VERSION 5.7 ;
  NOWIREEXTENSIONATPIN ON ;
  DIVIDERCHAR "/" ;
  BUSBITCHARS "[]" ;
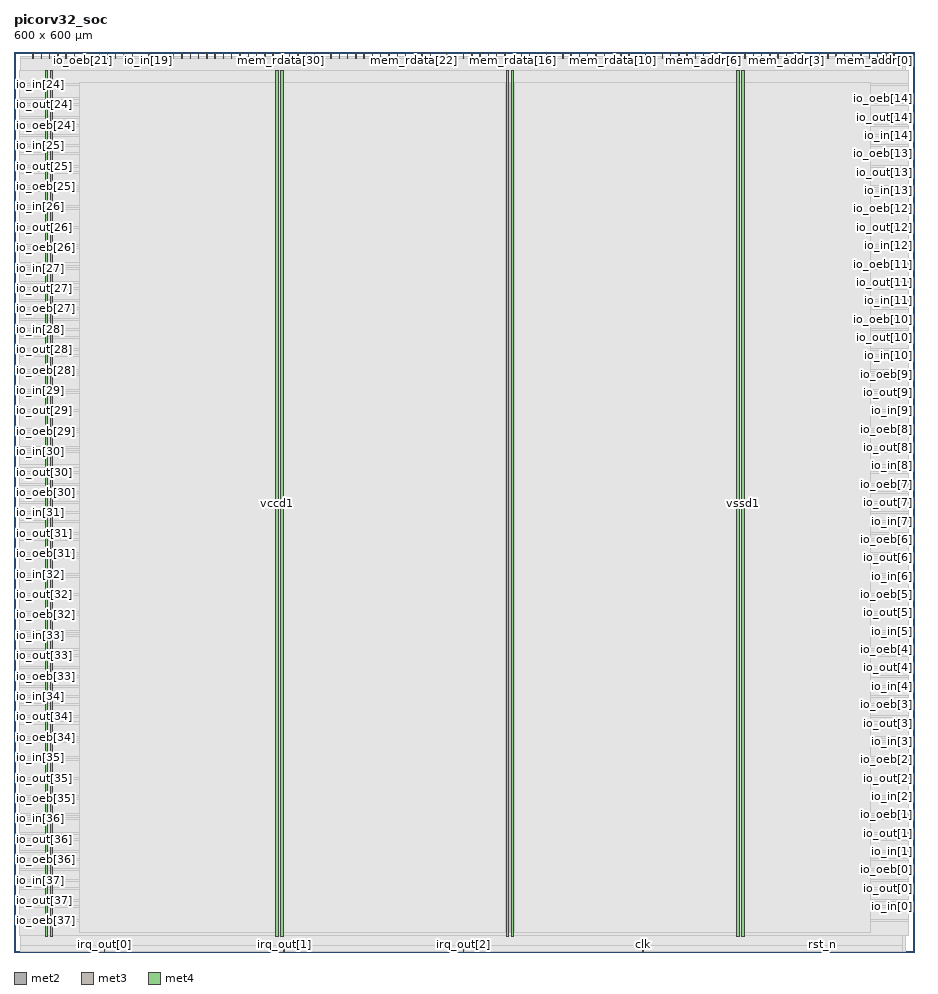
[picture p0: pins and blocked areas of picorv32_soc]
MACRO picorv32_soc
  CLASS BLOCK ;
  FOREIGN picorv32_soc ;
  ORIGIN 0.000 0.000 ;
  SIZE 600.000 BY 600.000 ;
  PIN clk
    DIRECTION INPUT ;
    USE SIGNAL ;
    ANTENNAGATEAREA 1.286700 ;
    ANTENNADIFFAREA 0.434700 ;
    PORT
      LAYER met2 ;
        RECT 419.150 0.000 419.430 4.000 ;
    END
  END clk
  PIN io_in[0]
    DIRECTION INPUT ;
    USE SIGNAL ;
    PORT
      LAYER met3 ;
        RECT 596.000 29.960 600.000 30.560 ;
    END
  END io_in[0]
  PIN io_in[10]
    DIRECTION INPUT ;
    USE SIGNAL ;
    PORT
      LAYER met3 ;
        RECT 596.000 397.160 600.000 397.760 ;
    END
  END io_in[10]
  PIN io_in[11]
    DIRECTION INPUT ;
    USE SIGNAL ;
    PORT
      LAYER met3 ;
        RECT 596.000 433.880 600.000 434.480 ;
    END
  END io_in[11]
  PIN io_in[12]
    DIRECTION INPUT ;
    USE SIGNAL ;
    PORT
      LAYER met3 ;
        RECT 596.000 470.600 600.000 471.200 ;
    END
  END io_in[12]
  PIN io_in[13]
    DIRECTION INPUT ;
    USE SIGNAL ;
    PORT
      LAYER met3 ;
        RECT 596.000 507.320 600.000 507.920 ;
    END
  END io_in[13]
  PIN io_in[14]
    DIRECTION INPUT ;
    USE SIGNAL ;
    PORT
      LAYER met3 ;
        RECT 596.000 544.040 600.000 544.640 ;
    END
  END io_in[14]
  PIN io_in[15]
    DIRECTION INPUT ;
    USE SIGNAL ;
    PORT
      LAYER met2 ;
        RECT 156.030 596.000 156.310 600.000 ;
    END
  END io_in[15]
  PIN io_in[16]
    DIRECTION INPUT ;
    USE SIGNAL ;
    PORT
      LAYER met2 ;
        RECT 139.470 596.000 139.750 600.000 ;
    END
  END io_in[16]
  PIN io_in[17]
    DIRECTION INPUT ;
    USE SIGNAL ;
    PORT
      LAYER met2 ;
        RECT 122.910 596.000 123.190 600.000 ;
    END
  END io_in[17]
  PIN io_in[18]
    DIRECTION INPUT ;
    USE SIGNAL ;
    PORT
      LAYER met2 ;
        RECT 106.350 596.000 106.630 600.000 ;
    END
  END io_in[18]
  PIN io_in[19]
    DIRECTION INPUT ;
    USE SIGNAL ;
    PORT
      LAYER met2 ;
        RECT 89.790 596.000 90.070 600.000 ;
    END
  END io_in[19]
  PIN io_in[1]
    DIRECTION INPUT ;
    USE SIGNAL ;
    PORT
      LAYER met3 ;
        RECT 596.000 66.680 600.000 67.280 ;
    END
  END io_in[1]
  PIN io_in[20]
    DIRECTION INPUT ;
    USE SIGNAL ;
    PORT
      LAYER met2 ;
        RECT 73.230 596.000 73.510 600.000 ;
    END
  END io_in[20]
  PIN io_in[21]
    DIRECTION INPUT ;
    USE SIGNAL ;
    ANTENNAGATEAREA 0.631200 ;
    ANTENNADIFFAREA 0.434700 ;
    PORT
      LAYER met2 ;
        RECT 56.670 596.000 56.950 600.000 ;
    END
  END io_in[21]
  PIN io_in[22]
    DIRECTION INPUT ;
    USE SIGNAL ;
    PORT
      LAYER met2 ;
        RECT 40.110 596.000 40.390 600.000 ;
    END
  END io_in[22]
  PIN io_in[23]
    DIRECTION INPUT ;
    USE SIGNAL ;
    PORT
      LAYER met2 ;
        RECT 23.550 596.000 23.830 600.000 ;
    END
  END io_in[23]
  PIN io_in[24]
    DIRECTION INPUT ;
    USE SIGNAL ;
    PORT
      LAYER met3 ;
        RECT 0.000 578.040 4.000 578.640 ;
    END
  END io_in[24]
  PIN io_in[25]
    DIRECTION INPUT ;
    USE SIGNAL ;
    PORT
      LAYER met3 ;
        RECT 0.000 537.240 4.000 537.840 ;
    END
  END io_in[25]
  PIN io_in[26]
    DIRECTION INPUT ;
    USE SIGNAL ;
    PORT
      LAYER met3 ;
        RECT 0.000 496.440 4.000 497.040 ;
    END
  END io_in[26]
  PIN io_in[27]
    DIRECTION INPUT ;
    USE SIGNAL ;
    PORT
      LAYER met3 ;
        RECT 0.000 455.640 4.000 456.240 ;
    END
  END io_in[27]
  PIN io_in[28]
    DIRECTION INPUT ;
    USE SIGNAL ;
    PORT
      LAYER met3 ;
        RECT 0.000 414.840 4.000 415.440 ;
    END
  END io_in[28]
  PIN io_in[29]
    DIRECTION INPUT ;
    USE SIGNAL ;
    PORT
      LAYER met3 ;
        RECT 0.000 374.040 4.000 374.640 ;
    END
  END io_in[29]
  PIN io_in[2]
    DIRECTION INPUT ;
    USE SIGNAL ;
    PORT
      LAYER met3 ;
        RECT 596.000 103.400 600.000 104.000 ;
    END
  END io_in[2]
  PIN io_in[30]
    DIRECTION INPUT ;
    USE SIGNAL ;
    PORT
      LAYER met3 ;
        RECT 0.000 333.240 4.000 333.840 ;
    END
  END io_in[30]
  PIN io_in[31]
    DIRECTION INPUT ;
    USE SIGNAL ;
    PORT
      LAYER met3 ;
        RECT 0.000 292.440 4.000 293.040 ;
    END
  END io_in[31]
  PIN io_in[32]
    DIRECTION INPUT ;
    USE SIGNAL ;
    PORT
      LAYER met3 ;
        RECT 0.000 251.640 4.000 252.240 ;
    END
  END io_in[32]
  PIN io_in[33]
    DIRECTION INPUT ;
    USE SIGNAL ;
    PORT
      LAYER met3 ;
        RECT 0.000 210.840 4.000 211.440 ;
    END
  END io_in[33]
  PIN io_in[34]
    DIRECTION INPUT ;
    USE SIGNAL ;
    PORT
      LAYER met3 ;
        RECT 0.000 170.040 4.000 170.640 ;
    END
  END io_in[34]
  PIN io_in[35]
    DIRECTION INPUT ;
    USE SIGNAL ;
    PORT
      LAYER met3 ;
        RECT 0.000 129.240 4.000 129.840 ;
    END
  END io_in[35]
  PIN io_in[36]
    DIRECTION INPUT ;
    USE SIGNAL ;
    PORT
      LAYER met3 ;
        RECT 0.000 88.440 4.000 89.040 ;
    END
  END io_in[36]
  PIN io_in[37]
    DIRECTION INPUT ;
    USE SIGNAL ;
    PORT
      LAYER met3 ;
        RECT 0.000 47.640 4.000 48.240 ;
    END
  END io_in[37]
  PIN io_in[3]
    DIRECTION INPUT ;
    USE SIGNAL ;
    PORT
      LAYER met3 ;
        RECT 596.000 140.120 600.000 140.720 ;
    END
  END io_in[3]
  PIN io_in[4]
    DIRECTION INPUT ;
    USE SIGNAL ;
    PORT
      LAYER met3 ;
        RECT 596.000 176.840 600.000 177.440 ;
    END
  END io_in[4]
  PIN io_in[5]
    DIRECTION INPUT ;
    USE SIGNAL ;
    PORT
      LAYER met3 ;
        RECT 596.000 213.560 600.000 214.160 ;
    END
  END io_in[5]
  PIN io_in[6]
    DIRECTION INPUT ;
    USE SIGNAL ;
    PORT
      LAYER met3 ;
        RECT 596.000 250.280 600.000 250.880 ;
    END
  END io_in[6]
  PIN io_in[7]
    DIRECTION INPUT ;
    USE SIGNAL ;
    PORT
      LAYER met3 ;
        RECT 596.000 287.000 600.000 287.600 ;
    END
  END io_in[7]
  PIN io_in[8]
    DIRECTION INPUT ;
    USE SIGNAL ;
    PORT
      LAYER met3 ;
        RECT 596.000 323.720 600.000 324.320 ;
    END
  END io_in[8]
  PIN io_in[9]
    DIRECTION INPUT ;
    USE SIGNAL ;
    PORT
      LAYER met3 ;
        RECT 596.000 360.440 600.000 361.040 ;
    END
  END io_in[9]
  PIN io_oeb[0]
    DIRECTION OUTPUT ;
    USE SIGNAL ;
    PORT
      LAYER met3 ;
        RECT 596.000 54.440 600.000 55.040 ;
    END
  END io_oeb[0]
  PIN io_oeb[10]
    DIRECTION OUTPUT ;
    USE SIGNAL ;
    PORT
      LAYER met3 ;
        RECT 596.000 421.640 600.000 422.240 ;
    END
  END io_oeb[10]
  PIN io_oeb[11]
    DIRECTION OUTPUT ;
    USE SIGNAL ;
    PORT
      LAYER met3 ;
        RECT 596.000 458.360 600.000 458.960 ;
    END
  END io_oeb[11]
  PIN io_oeb[12]
    DIRECTION OUTPUT ;
    USE SIGNAL ;
    PORT
      LAYER met3 ;
        RECT 596.000 495.080 600.000 495.680 ;
    END
  END io_oeb[12]
  PIN io_oeb[13]
    DIRECTION OUTPUT ;
    USE SIGNAL ;
    PORT
      LAYER met3 ;
        RECT 596.000 531.800 600.000 532.400 ;
    END
  END io_oeb[13]
  PIN io_oeb[14]
    DIRECTION OUTPUT ;
    USE SIGNAL ;
    PORT
      LAYER met3 ;
        RECT 596.000 568.520 600.000 569.120 ;
    END
  END io_oeb[14]
  PIN io_oeb[15]
    DIRECTION OUTPUT ;
    USE SIGNAL ;
    PORT
      LAYER met2 ;
        RECT 144.990 596.000 145.270 600.000 ;
    END
  END io_oeb[15]
  PIN io_oeb[16]
    DIRECTION OUTPUT ;
    USE SIGNAL ;
    PORT
      LAYER met2 ;
        RECT 128.430 596.000 128.710 600.000 ;
    END
  END io_oeb[16]
  PIN io_oeb[17]
    DIRECTION OUTPUT ;
    USE SIGNAL ;
    PORT
      LAYER met2 ;
        RECT 111.870 596.000 112.150 600.000 ;
    END
  END io_oeb[17]
  PIN io_oeb[18]
    DIRECTION OUTPUT ;
    USE SIGNAL ;
    PORT
      LAYER met2 ;
        RECT 95.310 596.000 95.590 600.000 ;
    END
  END io_oeb[18]
  PIN io_oeb[19]
    DIRECTION OUTPUT ;
    USE SIGNAL ;
    PORT
      LAYER met2 ;
        RECT 78.750 596.000 79.030 600.000 ;
    END
  END io_oeb[19]
  PIN io_oeb[1]
    DIRECTION OUTPUT ;
    USE SIGNAL ;
    PORT
      LAYER met3 ;
        RECT 596.000 91.160 600.000 91.760 ;
    END
  END io_oeb[1]
  PIN io_oeb[20]
    DIRECTION OUTPUT ;
    USE SIGNAL ;
    PORT
      LAYER met2 ;
        RECT 62.190 596.000 62.470 600.000 ;
    END
  END io_oeb[20]
  PIN io_oeb[21]
    DIRECTION OUTPUT ;
    USE SIGNAL ;
    PORT
      LAYER met2 ;
        RECT 45.630 596.000 45.910 600.000 ;
    END
  END io_oeb[21]
  PIN io_oeb[22]
    DIRECTION OUTPUT ;
    USE SIGNAL ;
    PORT
      LAYER met2 ;
        RECT 29.070 596.000 29.350 600.000 ;
    END
  END io_oeb[22]
  PIN io_oeb[23]
    DIRECTION OUTPUT ;
    USE SIGNAL ;
    PORT
      LAYER met2 ;
        RECT 12.510 596.000 12.790 600.000 ;
    END
  END io_oeb[23]
  PIN io_oeb[24]
    DIRECTION OUTPUT ;
    USE SIGNAL ;
    PORT
      LAYER met3 ;
        RECT 0.000 550.840 4.000 551.440 ;
    END
  END io_oeb[24]
  PIN io_oeb[25]
    DIRECTION OUTPUT ;
    USE SIGNAL ;
    PORT
      LAYER met3 ;
        RECT 0.000 510.040 4.000 510.640 ;
    END
  END io_oeb[25]
  PIN io_oeb[26]
    DIRECTION OUTPUT ;
    USE SIGNAL ;
    PORT
      LAYER met3 ;
        RECT 0.000 469.240 4.000 469.840 ;
    END
  END io_oeb[26]
  PIN io_oeb[27]
    DIRECTION OUTPUT ;
    USE SIGNAL ;
    PORT
      LAYER met3 ;
        RECT 0.000 428.440 4.000 429.040 ;
    END
  END io_oeb[27]
  PIN io_oeb[28]
    DIRECTION OUTPUT ;
    USE SIGNAL ;
    PORT
      LAYER met3 ;
        RECT 0.000 387.640 4.000 388.240 ;
    END
  END io_oeb[28]
  PIN io_oeb[29]
    DIRECTION OUTPUT ;
    USE SIGNAL ;
    PORT
      LAYER met3 ;
        RECT 0.000 346.840 4.000 347.440 ;
    END
  END io_oeb[29]
  PIN io_oeb[2]
    DIRECTION OUTPUT ;
    USE SIGNAL ;
    PORT
      LAYER met3 ;
        RECT 596.000 127.880 600.000 128.480 ;
    END
  END io_oeb[2]
  PIN io_oeb[30]
    DIRECTION OUTPUT ;
    USE SIGNAL ;
    PORT
      LAYER met3 ;
        RECT 0.000 306.040 4.000 306.640 ;
    END
  END io_oeb[30]
  PIN io_oeb[31]
    DIRECTION OUTPUT ;
    USE SIGNAL ;
    PORT
      LAYER met3 ;
        RECT 0.000 265.240 4.000 265.840 ;
    END
  END io_oeb[31]
  PIN io_oeb[32]
    DIRECTION OUTPUT ;
    USE SIGNAL ;
    PORT
      LAYER met3 ;
        RECT 0.000 224.440 4.000 225.040 ;
    END
  END io_oeb[32]
  PIN io_oeb[33]
    DIRECTION OUTPUT ;
    USE SIGNAL ;
    PORT
      LAYER met3 ;
        RECT 0.000 183.640 4.000 184.240 ;
    END
  END io_oeb[33]
  PIN io_oeb[34]
    DIRECTION OUTPUT ;
    USE SIGNAL ;
    PORT
      LAYER met3 ;
        RECT 0.000 142.840 4.000 143.440 ;
    END
  END io_oeb[34]
  PIN io_oeb[35]
    DIRECTION OUTPUT ;
    USE SIGNAL ;
    PORT
      LAYER met3 ;
        RECT 0.000 102.040 4.000 102.640 ;
    END
  END io_oeb[35]
  PIN io_oeb[36]
    DIRECTION OUTPUT ;
    USE SIGNAL ;
    PORT
      LAYER met3 ;
        RECT 0.000 61.240 4.000 61.840 ;
    END
  END io_oeb[36]
  PIN io_oeb[37]
    DIRECTION OUTPUT ;
    USE SIGNAL ;
    PORT
      LAYER met3 ;
        RECT 0.000 20.440 4.000 21.040 ;
    END
  END io_oeb[37]
  PIN io_oeb[3]
    DIRECTION OUTPUT ;
    USE SIGNAL ;
    PORT
      LAYER met3 ;
        RECT 596.000 164.600 600.000 165.200 ;
    END
  END io_oeb[3]
  PIN io_oeb[4]
    DIRECTION OUTPUT ;
    USE SIGNAL ;
    PORT
      LAYER met3 ;
        RECT 596.000 201.320 600.000 201.920 ;
    END
  END io_oeb[4]
  PIN io_oeb[5]
    DIRECTION OUTPUT ;
    USE SIGNAL ;
    PORT
      LAYER met3 ;
        RECT 596.000 238.040 600.000 238.640 ;
    END
  END io_oeb[5]
  PIN io_oeb[6]
    DIRECTION OUTPUT ;
    USE SIGNAL ;
    PORT
      LAYER met3 ;
        RECT 596.000 274.760 600.000 275.360 ;
    END
  END io_oeb[6]
  PIN io_oeb[7]
    DIRECTION OUTPUT ;
    USE SIGNAL ;
    PORT
      LAYER met3 ;
        RECT 596.000 311.480 600.000 312.080 ;
    END
  END io_oeb[7]
  PIN io_oeb[8]
    DIRECTION OUTPUT ;
    USE SIGNAL ;
    PORT
      LAYER met3 ;
        RECT 596.000 348.200 600.000 348.800 ;
    END
  END io_oeb[8]
  PIN io_oeb[9]
    DIRECTION OUTPUT ;
    USE SIGNAL ;
    PORT
      LAYER met3 ;
        RECT 596.000 384.920 600.000 385.520 ;
    END
  END io_oeb[9]
  PIN io_out[0]
    DIRECTION OUTPUT ;
    USE SIGNAL ;
    PORT
      LAYER met3 ;
        RECT 596.000 42.200 600.000 42.800 ;
    END
  END io_out[0]
  PIN io_out[10]
    DIRECTION OUTPUT ;
    USE SIGNAL ;
    PORT
      LAYER met3 ;
        RECT 596.000 409.400 600.000 410.000 ;
    END
  END io_out[10]
  PIN io_out[11]
    DIRECTION OUTPUT ;
    USE SIGNAL ;
    PORT
      LAYER met3 ;
        RECT 596.000 446.120 600.000 446.720 ;
    END
  END io_out[11]
  PIN io_out[12]
    DIRECTION OUTPUT ;
    USE SIGNAL ;
    PORT
      LAYER met3 ;
        RECT 596.000 482.840 600.000 483.440 ;
    END
  END io_out[12]
  PIN io_out[13]
    DIRECTION OUTPUT ;
    USE SIGNAL ;
    PORT
      LAYER met3 ;
        RECT 596.000 519.560 600.000 520.160 ;
    END
  END io_out[13]
  PIN io_out[14]
    DIRECTION OUTPUT ;
    USE SIGNAL ;
    PORT
      LAYER met3 ;
        RECT 596.000 556.280 600.000 556.880 ;
    END
  END io_out[14]
  PIN io_out[15]
    DIRECTION OUTPUT ;
    USE SIGNAL ;
    PORT
      LAYER met2 ;
        RECT 150.510 596.000 150.790 600.000 ;
    END
  END io_out[15]
  PIN io_out[16]
    DIRECTION OUTPUT ;
    USE SIGNAL ;
    PORT
      LAYER met2 ;
        RECT 133.950 596.000 134.230 600.000 ;
    END
  END io_out[16]
  PIN io_out[17]
    DIRECTION OUTPUT ;
    USE SIGNAL ;
    PORT
      LAYER met2 ;
        RECT 117.390 596.000 117.670 600.000 ;
    END
  END io_out[17]
  PIN io_out[18]
    DIRECTION OUTPUT ;
    USE SIGNAL ;
    PORT
      LAYER met2 ;
        RECT 100.830 596.000 101.110 600.000 ;
    END
  END io_out[18]
  PIN io_out[19]
    DIRECTION OUTPUT ;
    USE SIGNAL ;
    PORT
      LAYER met2 ;
        RECT 84.270 596.000 84.550 600.000 ;
    END
  END io_out[19]
  PIN io_out[1]
    DIRECTION OUTPUT ;
    USE SIGNAL ;
    PORT
      LAYER met3 ;
        RECT 596.000 78.920 600.000 79.520 ;
    END
  END io_out[1]
  PIN io_out[20]
    DIRECTION OUTPUT ;
    USE SIGNAL ;
    ANTENNADIFFAREA 2.673000 ;
    PORT
      LAYER met2 ;
        RECT 67.710 596.000 67.990 600.000 ;
    END
  END io_out[20]
  PIN io_out[21]
    DIRECTION OUTPUT ;
    USE SIGNAL ;
    PORT
      LAYER met2 ;
        RECT 51.150 596.000 51.430 600.000 ;
    END
  END io_out[21]
  PIN io_out[22]
    DIRECTION OUTPUT ;
    USE SIGNAL ;
    PORT
      LAYER met2 ;
        RECT 34.590 596.000 34.870 600.000 ;
    END
  END io_out[22]
  PIN io_out[23]
    DIRECTION OUTPUT ;
    USE SIGNAL ;
    PORT
      LAYER met2 ;
        RECT 18.030 596.000 18.310 600.000 ;
    END
  END io_out[23]
  PIN io_out[24]
    DIRECTION OUTPUT ;
    USE SIGNAL ;
    PORT
      LAYER met3 ;
        RECT 0.000 564.440 4.000 565.040 ;
    END
  END io_out[24]
  PIN io_out[25]
    DIRECTION OUTPUT ;
    USE SIGNAL ;
    PORT
      LAYER met3 ;
        RECT 0.000 523.640 4.000 524.240 ;
    END
  END io_out[25]
  PIN io_out[26]
    DIRECTION OUTPUT ;
    USE SIGNAL ;
    PORT
      LAYER met3 ;
        RECT 0.000 482.840 4.000 483.440 ;
    END
  END io_out[26]
  PIN io_out[27]
    DIRECTION OUTPUT ;
    USE SIGNAL ;
    PORT
      LAYER met3 ;
        RECT 0.000 442.040 4.000 442.640 ;
    END
  END io_out[27]
  PIN io_out[28]
    DIRECTION OUTPUT ;
    USE SIGNAL ;
    PORT
      LAYER met3 ;
        RECT 0.000 401.240 4.000 401.840 ;
    END
  END io_out[28]
  PIN io_out[29]
    DIRECTION OUTPUT ;
    USE SIGNAL ;
    PORT
      LAYER met3 ;
        RECT 0.000 360.440 4.000 361.040 ;
    END
  END io_out[29]
  PIN io_out[2]
    DIRECTION OUTPUT ;
    USE SIGNAL ;
    PORT
      LAYER met3 ;
        RECT 596.000 115.640 600.000 116.240 ;
    END
  END io_out[2]
  PIN io_out[30]
    DIRECTION OUTPUT ;
    USE SIGNAL ;
    PORT
      LAYER met3 ;
        RECT 0.000 319.640 4.000 320.240 ;
    END
  END io_out[30]
  PIN io_out[31]
    DIRECTION OUTPUT ;
    USE SIGNAL ;
    PORT
      LAYER met3 ;
        RECT 0.000 278.840 4.000 279.440 ;
    END
  END io_out[31]
  PIN io_out[32]
    DIRECTION OUTPUT ;
    USE SIGNAL ;
    PORT
      LAYER met3 ;
        RECT 0.000 238.040 4.000 238.640 ;
    END
  END io_out[32]
  PIN io_out[33]
    DIRECTION OUTPUT ;
    USE SIGNAL ;
    PORT
      LAYER met3 ;
        RECT 0.000 197.240 4.000 197.840 ;
    END
  END io_out[33]
  PIN io_out[34]
    DIRECTION OUTPUT ;
    USE SIGNAL ;
    PORT
      LAYER met3 ;
        RECT 0.000 156.440 4.000 157.040 ;
    END
  END io_out[34]
  PIN io_out[35]
    DIRECTION OUTPUT ;
    USE SIGNAL ;
    PORT
      LAYER met3 ;
        RECT 0.000 115.640 4.000 116.240 ;
    END
  END io_out[35]
  PIN io_out[36]
    DIRECTION OUTPUT ;
    USE SIGNAL ;
    PORT
      LAYER met3 ;
        RECT 0.000 74.840 4.000 75.440 ;
    END
  END io_out[36]
  PIN io_out[37]
    DIRECTION OUTPUT ;
    USE SIGNAL ;
    PORT
      LAYER met3 ;
        RECT 0.000 34.040 4.000 34.640 ;
    END
  END io_out[37]
  PIN io_out[3]
    DIRECTION OUTPUT ;
    USE SIGNAL ;
    PORT
      LAYER met3 ;
        RECT 596.000 152.360 600.000 152.960 ;
    END
  END io_out[3]
  PIN io_out[4]
    DIRECTION OUTPUT ;
    USE SIGNAL ;
    PORT
      LAYER met3 ;
        RECT 596.000 189.080 600.000 189.680 ;
    END
  END io_out[4]
  PIN io_out[5]
    DIRECTION OUTPUT ;
    USE SIGNAL ;
    PORT
      LAYER met3 ;
        RECT 596.000 225.800 600.000 226.400 ;
    END
  END io_out[5]
  PIN io_out[6]
    DIRECTION OUTPUT ;
    USE SIGNAL ;
    PORT
      LAYER met3 ;
        RECT 596.000 262.520 600.000 263.120 ;
    END
  END io_out[6]
  PIN io_out[7]
    DIRECTION OUTPUT ;
    USE SIGNAL ;
    PORT
      LAYER met3 ;
        RECT 596.000 299.240 600.000 299.840 ;
    END
  END io_out[7]
  PIN io_out[8]
    DIRECTION OUTPUT ;
    USE SIGNAL ;
    PORT
      LAYER met3 ;
        RECT 596.000 335.960 600.000 336.560 ;
    END
  END io_out[8]
  PIN io_out[9]
    DIRECTION OUTPUT ;
    USE SIGNAL ;
    PORT
      LAYER met3 ;
        RECT 596.000 372.680 600.000 373.280 ;
    END
  END io_out[9]
  PIN irq_out[0]
    DIRECTION OUTPUT ;
    USE SIGNAL ;
    PORT
      LAYER met2 ;
        RECT 60.350 0.000 60.630 4.000 ;
    END
  END irq_out[0]
  PIN irq_out[1]
    DIRECTION OUTPUT ;
    USE SIGNAL ;
    ANTENNADIFFAREA 2.673000 ;
    PORT
      LAYER met2 ;
        RECT 179.950 0.000 180.230 4.000 ;
    END
  END irq_out[1]
  PIN irq_out[2]
    DIRECTION OUTPUT ;
    USE SIGNAL ;
    PORT
      LAYER met2 ;
        RECT 299.550 0.000 299.830 4.000 ;
    END
  END irq_out[2]
  PIN mem_addr[0]
    DIRECTION OUTPUT ;
    USE SIGNAL ;
    ANTENNADIFFAREA 2.673000 ;
    PORT
      LAYER met2 ;
        RECT 581.070 596.000 581.350 600.000 ;
    END
  END mem_addr[0]
  PIN mem_addr[1]
    DIRECTION OUTPUT ;
    USE SIGNAL ;
    ANTENNADIFFAREA 2.673000 ;
    PORT
      LAYER met2 ;
        RECT 558.990 596.000 559.270 600.000 ;
    END
  END mem_addr[1]
  PIN mem_addr[2]
    DIRECTION OUTPUT ;
    USE SIGNAL ;
    ANTENNADIFFAREA 2.673000 ;
    PORT
      LAYER met2 ;
        RECT 536.910 596.000 537.190 600.000 ;
    END
  END mem_addr[2]
  PIN mem_addr[3]
    DIRECTION OUTPUT ;
    USE SIGNAL ;
    ANTENNADIFFAREA 2.673000 ;
    PORT
      LAYER met2 ;
        RECT 514.830 596.000 515.110 600.000 ;
    END
  END mem_addr[3]
  PIN mem_addr[4]
    DIRECTION OUTPUT ;
    USE SIGNAL ;
    ANTENNADIFFAREA 2.673000 ;
    PORT
      LAYER met2 ;
        RECT 492.750 596.000 493.030 600.000 ;
    END
  END mem_addr[4]
  PIN mem_addr[5]
    DIRECTION OUTPUT ;
    USE SIGNAL ;
    ANTENNADIFFAREA 2.673000 ;
    PORT
      LAYER met2 ;
        RECT 476.190 596.000 476.470 600.000 ;
    END
  END mem_addr[5]
  PIN mem_addr[6]
    DIRECTION OUTPUT ;
    USE SIGNAL ;
    ANTENNADIFFAREA 2.673000 ;
    PORT
      LAYER met2 ;
        RECT 459.630 596.000 459.910 600.000 ;
    END
  END mem_addr[6]
  PIN mem_addr[7]
    DIRECTION OUTPUT ;
    USE SIGNAL ;
    ANTENNADIFFAREA 2.673000 ;
    PORT
      LAYER met2 ;
        RECT 443.070 596.000 443.350 600.000 ;
    END
  END mem_addr[7]
  PIN mem_addr[8]
    DIRECTION OUTPUT ;
    USE SIGNAL ;
    ANTENNADIFFAREA 2.673000 ;
    PORT
      LAYER met2 ;
        RECT 426.510 596.000 426.790 600.000 ;
    END
  END mem_addr[8]
  PIN mem_en
    DIRECTION OUTPUT ;
    USE SIGNAL ;
    ANTENNADIFFAREA 2.673000 ;
    PORT
      LAYER met2 ;
        RECT 586.590 596.000 586.870 600.000 ;
    END
  END mem_en
  PIN mem_rdata[0]
    DIRECTION INPUT ;
    USE SIGNAL ;
    ANTENNAGATEAREA 0.631200 ;
    ANTENNADIFFAREA 0.434700 ;
    PORT
      LAYER met2 ;
        RECT 575.550 596.000 575.830 600.000 ;
    END
  END mem_rdata[0]
  PIN mem_rdata[10]
    DIRECTION INPUT ;
    USE SIGNAL ;
    ANTENNAGATEAREA 0.631200 ;
    ANTENNADIFFAREA 0.434700 ;
    PORT
      LAYER met2 ;
        RECT 398.910 596.000 399.190 600.000 ;
    END
  END mem_rdata[10]
  PIN mem_rdata[11]
    DIRECTION INPUT ;
    USE SIGNAL ;
    ANTENNAGATEAREA 0.631200 ;
    ANTENNADIFFAREA 0.434700 ;
    PORT
      LAYER met2 ;
        RECT 387.870 596.000 388.150 600.000 ;
    END
  END mem_rdata[11]
  PIN mem_rdata[12]
    DIRECTION INPUT ;
    USE SIGNAL ;
    ANTENNAGATEAREA 0.631200 ;
    ANTENNADIFFAREA 0.434700 ;
    PORT
      LAYER met2 ;
        RECT 376.830 596.000 377.110 600.000 ;
    END
  END mem_rdata[12]
  PIN mem_rdata[13]
    DIRECTION INPUT ;
    USE SIGNAL ;
    ANTENNAGATEAREA 0.631200 ;
    ANTENNADIFFAREA 0.434700 ;
    PORT
      LAYER met2 ;
        RECT 365.790 596.000 366.070 600.000 ;
    END
  END mem_rdata[13]
  PIN mem_rdata[14]
    DIRECTION INPUT ;
    USE SIGNAL ;
    ANTENNAGATEAREA 0.631200 ;
    ANTENNADIFFAREA 0.434700 ;
    PORT
      LAYER met2 ;
        RECT 354.750 596.000 355.030 600.000 ;
    END
  END mem_rdata[14]
  PIN mem_rdata[15]
    DIRECTION INPUT ;
    USE SIGNAL ;
    ANTENNAGATEAREA 0.631200 ;
    ANTENNADIFFAREA 0.434700 ;
    PORT
      LAYER met2 ;
        RECT 343.710 596.000 343.990 600.000 ;
    END
  END mem_rdata[15]
  PIN mem_rdata[16]
    DIRECTION INPUT ;
    USE SIGNAL ;
    ANTENNAGATEAREA 0.631200 ;
    ANTENNADIFFAREA 0.434700 ;
    PORT
      LAYER met2 ;
        RECT 332.670 596.000 332.950 600.000 ;
    END
  END mem_rdata[16]
  PIN mem_rdata[17]
    DIRECTION INPUT ;
    USE SIGNAL ;
    ANTENNAGATEAREA 0.631200 ;
    ANTENNADIFFAREA 0.434700 ;
    PORT
      LAYER met2 ;
        RECT 321.630 596.000 321.910 600.000 ;
    END
  END mem_rdata[17]
  PIN mem_rdata[18]
    DIRECTION INPUT ;
    USE SIGNAL ;
    ANTENNAGATEAREA 0.631200 ;
    ANTENNADIFFAREA 0.434700 ;
    PORT
      LAYER met2 ;
        RECT 310.590 596.000 310.870 600.000 ;
    END
  END mem_rdata[18]
  PIN mem_rdata[19]
    DIRECTION INPUT ;
    USE SIGNAL ;
    ANTENNAGATEAREA 0.631200 ;
    ANTENNADIFFAREA 0.434700 ;
    PORT
      LAYER met2 ;
        RECT 299.550 596.000 299.830 600.000 ;
    END
  END mem_rdata[19]
  PIN mem_rdata[1]
    DIRECTION INPUT ;
    USE SIGNAL ;
    ANTENNAGATEAREA 0.631200 ;
    ANTENNADIFFAREA 0.434700 ;
    PORT
      LAYER met2 ;
        RECT 553.470 596.000 553.750 600.000 ;
    END
  END mem_rdata[1]
  PIN mem_rdata[20]
    DIRECTION INPUT ;
    USE SIGNAL ;
    ANTENNAGATEAREA 0.631200 ;
    ANTENNADIFFAREA 0.434700 ;
    PORT
      LAYER met2 ;
        RECT 288.510 596.000 288.790 600.000 ;
    END
  END mem_rdata[20]
  PIN mem_rdata[21]
    DIRECTION INPUT ;
    USE SIGNAL ;
    ANTENNAGATEAREA 0.631200 ;
    ANTENNADIFFAREA 0.434700 ;
    PORT
      LAYER met2 ;
        RECT 277.470 596.000 277.750 600.000 ;
    END
  END mem_rdata[21]
  PIN mem_rdata[22]
    DIRECTION INPUT ;
    USE SIGNAL ;
    ANTENNAGATEAREA 0.631200 ;
    ANTENNADIFFAREA 0.434700 ;
    PORT
      LAYER met2 ;
        RECT 266.430 596.000 266.710 600.000 ;
    END
  END mem_rdata[22]
  PIN mem_rdata[23]
    DIRECTION INPUT ;
    USE SIGNAL ;
    ANTENNAGATEAREA 0.631200 ;
    ANTENNADIFFAREA 0.434700 ;
    PORT
      LAYER met2 ;
        RECT 255.390 596.000 255.670 600.000 ;
    END
  END mem_rdata[23]
  PIN mem_rdata[24]
    DIRECTION INPUT ;
    USE SIGNAL ;
    ANTENNAGATEAREA 0.631200 ;
    ANTENNADIFFAREA 0.434700 ;
    PORT
      LAYER met2 ;
        RECT 244.350 596.000 244.630 600.000 ;
    END
  END mem_rdata[24]
  PIN mem_rdata[25]
    DIRECTION INPUT ;
    USE SIGNAL ;
    ANTENNAGATEAREA 0.631200 ;
    ANTENNADIFFAREA 0.434700 ;
    PORT
      LAYER met2 ;
        RECT 233.310 596.000 233.590 600.000 ;
    END
  END mem_rdata[25]
  PIN mem_rdata[26]
    DIRECTION INPUT ;
    USE SIGNAL ;
    ANTENNAGATEAREA 0.631200 ;
    ANTENNADIFFAREA 0.434700 ;
    PORT
      LAYER met2 ;
        RECT 222.270 596.000 222.550 600.000 ;
    END
  END mem_rdata[26]
  PIN mem_rdata[27]
    DIRECTION INPUT ;
    USE SIGNAL ;
    ANTENNAGATEAREA 0.631200 ;
    ANTENNADIFFAREA 0.434700 ;
    PORT
      LAYER met2 ;
        RECT 211.230 596.000 211.510 600.000 ;
    END
  END mem_rdata[27]
  PIN mem_rdata[28]
    DIRECTION INPUT ;
    USE SIGNAL ;
    ANTENNAGATEAREA 0.631200 ;
    ANTENNADIFFAREA 0.434700 ;
    PORT
      LAYER met2 ;
        RECT 200.190 596.000 200.470 600.000 ;
    END
  END mem_rdata[28]
  PIN mem_rdata[29]
    DIRECTION INPUT ;
    USE SIGNAL ;
    ANTENNAGATEAREA 0.631200 ;
    ANTENNADIFFAREA 0.434700 ;
    PORT
      LAYER met2 ;
        RECT 189.150 596.000 189.430 600.000 ;
    END
  END mem_rdata[29]
  PIN mem_rdata[2]
    DIRECTION INPUT ;
    USE SIGNAL ;
    ANTENNAGATEAREA 0.631200 ;
    ANTENNADIFFAREA 0.434700 ;
    PORT
      LAYER met2 ;
        RECT 531.390 596.000 531.670 600.000 ;
    END
  END mem_rdata[2]
  PIN mem_rdata[30]
    DIRECTION INPUT ;
    USE SIGNAL ;
    ANTENNAGATEAREA 0.631200 ;
    ANTENNADIFFAREA 0.434700 ;
    PORT
      LAYER met2 ;
        RECT 178.110 596.000 178.390 600.000 ;
    END
  END mem_rdata[30]
  PIN mem_rdata[31]
    DIRECTION INPUT ;
    USE SIGNAL ;
    ANTENNAGATEAREA 0.631200 ;
    ANTENNADIFFAREA 0.434700 ;
    PORT
      LAYER met2 ;
        RECT 167.070 596.000 167.350 600.000 ;
    END
  END mem_rdata[31]
  PIN mem_rdata[3]
    DIRECTION INPUT ;
    USE SIGNAL ;
    ANTENNAGATEAREA 0.631200 ;
    ANTENNADIFFAREA 0.434700 ;
    PORT
      LAYER met2 ;
        RECT 509.310 596.000 509.590 600.000 ;
    END
  END mem_rdata[3]
  PIN mem_rdata[4]
    DIRECTION INPUT ;
    USE SIGNAL ;
    ANTENNAGATEAREA 0.631200 ;
    ANTENNADIFFAREA 0.434700 ;
    PORT
      LAYER met2 ;
        RECT 487.230 596.000 487.510 600.000 ;
    END
  END mem_rdata[4]
  PIN mem_rdata[5]
    DIRECTION INPUT ;
    USE SIGNAL ;
    ANTENNAGATEAREA 0.631200 ;
    ANTENNADIFFAREA 0.434700 ;
    PORT
      LAYER met2 ;
        RECT 470.670 596.000 470.950 600.000 ;
    END
  END mem_rdata[5]
  PIN mem_rdata[6]
    DIRECTION INPUT ;
    USE SIGNAL ;
    ANTENNAGATEAREA 0.631200 ;
    ANTENNADIFFAREA 0.434700 ;
    PORT
      LAYER met2 ;
        RECT 454.110 596.000 454.390 600.000 ;
    END
  END mem_rdata[6]
  PIN mem_rdata[7]
    DIRECTION INPUT ;
    USE SIGNAL ;
    ANTENNAGATEAREA 0.631200 ;
    ANTENNADIFFAREA 0.434700 ;
    PORT
      LAYER met2 ;
        RECT 437.550 596.000 437.830 600.000 ;
    END
  END mem_rdata[7]
  PIN mem_rdata[8]
    DIRECTION INPUT ;
    USE SIGNAL ;
    ANTENNAGATEAREA 0.631200 ;
    ANTENNADIFFAREA 0.434700 ;
    PORT
      LAYER met2 ;
        RECT 420.990 596.000 421.270 600.000 ;
    END
  END mem_rdata[8]
  PIN mem_rdata[9]
    DIRECTION INPUT ;
    USE SIGNAL ;
    ANTENNAGATEAREA 0.631200 ;
    ANTENNADIFFAREA 0.434700 ;
    PORT
      LAYER met2 ;
        RECT 409.950 596.000 410.230 600.000 ;
    END
  END mem_rdata[9]
  PIN mem_wdata[0]
    DIRECTION OUTPUT ;
    USE SIGNAL ;
    ANTENNADIFFAREA 2.673000 ;
    PORT
      LAYER met2 ;
        RECT 570.030 596.000 570.310 600.000 ;
    END
  END mem_wdata[0]
  PIN mem_wdata[10]
    DIRECTION OUTPUT ;
    USE SIGNAL ;
    ANTENNADIFFAREA 2.673000 ;
    PORT
      LAYER met2 ;
        RECT 393.390 596.000 393.670 600.000 ;
    END
  END mem_wdata[10]
  PIN mem_wdata[11]
    DIRECTION OUTPUT ;
    USE SIGNAL ;
    ANTENNADIFFAREA 2.673000 ;
    PORT
      LAYER met2 ;
        RECT 382.350 596.000 382.630 600.000 ;
    END
  END mem_wdata[11]
  PIN mem_wdata[12]
    DIRECTION OUTPUT ;
    USE SIGNAL ;
    ANTENNADIFFAREA 2.673000 ;
    PORT
      LAYER met2 ;
        RECT 371.310 596.000 371.590 600.000 ;
    END
  END mem_wdata[12]
  PIN mem_wdata[13]
    DIRECTION OUTPUT ;
    USE SIGNAL ;
    ANTENNADIFFAREA 2.673000 ;
    PORT
      LAYER met2 ;
        RECT 360.270 596.000 360.550 600.000 ;
    END
  END mem_wdata[13]
  PIN mem_wdata[14]
    DIRECTION OUTPUT ;
    USE SIGNAL ;
    ANTENNADIFFAREA 2.673000 ;
    PORT
      LAYER met2 ;
        RECT 349.230 596.000 349.510 600.000 ;
    END
  END mem_wdata[14]
  PIN mem_wdata[15]
    DIRECTION OUTPUT ;
    USE SIGNAL ;
    ANTENNADIFFAREA 2.673000 ;
    PORT
      LAYER met2 ;
        RECT 338.190 596.000 338.470 600.000 ;
    END
  END mem_wdata[15]
  PIN mem_wdata[16]
    DIRECTION OUTPUT ;
    USE SIGNAL ;
    ANTENNADIFFAREA 2.673000 ;
    PORT
      LAYER met2 ;
        RECT 327.150 596.000 327.430 600.000 ;
    END
  END mem_wdata[16]
  PIN mem_wdata[17]
    DIRECTION OUTPUT ;
    USE SIGNAL ;
    ANTENNADIFFAREA 2.673000 ;
    PORT
      LAYER met2 ;
        RECT 316.110 596.000 316.390 600.000 ;
    END
  END mem_wdata[17]
  PIN mem_wdata[18]
    DIRECTION OUTPUT ;
    USE SIGNAL ;
    ANTENNADIFFAREA 2.673000 ;
    PORT
      LAYER met2 ;
        RECT 305.070 596.000 305.350 600.000 ;
    END
  END mem_wdata[18]
  PIN mem_wdata[19]
    DIRECTION OUTPUT ;
    USE SIGNAL ;
    ANTENNADIFFAREA 2.673000 ;
    PORT
      LAYER met2 ;
        RECT 294.030 596.000 294.310 600.000 ;
    END
  END mem_wdata[19]
  PIN mem_wdata[1]
    DIRECTION OUTPUT ;
    USE SIGNAL ;
    ANTENNADIFFAREA 2.673000 ;
    PORT
      LAYER met2 ;
        RECT 547.950 596.000 548.230 600.000 ;
    END
  END mem_wdata[1]
  PIN mem_wdata[20]
    DIRECTION OUTPUT ;
    USE SIGNAL ;
    ANTENNADIFFAREA 2.673000 ;
    PORT
      LAYER met2 ;
        RECT 282.990 596.000 283.270 600.000 ;
    END
  END mem_wdata[20]
  PIN mem_wdata[21]
    DIRECTION OUTPUT ;
    USE SIGNAL ;
    ANTENNADIFFAREA 2.673000 ;
    PORT
      LAYER met2 ;
        RECT 271.950 596.000 272.230 600.000 ;
    END
  END mem_wdata[21]
  PIN mem_wdata[22]
    DIRECTION OUTPUT ;
    USE SIGNAL ;
    ANTENNADIFFAREA 2.673000 ;
    PORT
      LAYER met2 ;
        RECT 260.910 596.000 261.190 600.000 ;
    END
  END mem_wdata[22]
  PIN mem_wdata[23]
    DIRECTION OUTPUT ;
    USE SIGNAL ;
    ANTENNADIFFAREA 2.673000 ;
    PORT
      LAYER met2 ;
        RECT 249.870 596.000 250.150 600.000 ;
    END
  END mem_wdata[23]
  PIN mem_wdata[24]
    DIRECTION OUTPUT ;
    USE SIGNAL ;
    ANTENNADIFFAREA 2.673000 ;
    PORT
      LAYER met2 ;
        RECT 238.830 596.000 239.110 600.000 ;
    END
  END mem_wdata[24]
  PIN mem_wdata[25]
    DIRECTION OUTPUT ;
    USE SIGNAL ;
    ANTENNADIFFAREA 2.673000 ;
    PORT
      LAYER met2 ;
        RECT 227.790 596.000 228.070 600.000 ;
    END
  END mem_wdata[25]
  PIN mem_wdata[26]
    DIRECTION OUTPUT ;
    USE SIGNAL ;
    ANTENNADIFFAREA 2.673000 ;
    PORT
      LAYER met2 ;
        RECT 216.750 596.000 217.030 600.000 ;
    END
  END mem_wdata[26]
  PIN mem_wdata[27]
    DIRECTION OUTPUT ;
    USE SIGNAL ;
    ANTENNADIFFAREA 2.673000 ;
    PORT
      LAYER met2 ;
        RECT 205.710 596.000 205.990 600.000 ;
    END
  END mem_wdata[27]
  PIN mem_wdata[28]
    DIRECTION OUTPUT ;
    USE SIGNAL ;
    ANTENNADIFFAREA 2.673000 ;
    PORT
      LAYER met2 ;
        RECT 194.670 596.000 194.950 600.000 ;
    END
  END mem_wdata[28]
  PIN mem_wdata[29]
    DIRECTION OUTPUT ;
    USE SIGNAL ;
    ANTENNADIFFAREA 2.673000 ;
    PORT
      LAYER met2 ;
        RECT 183.630 596.000 183.910 600.000 ;
    END
  END mem_wdata[29]
  PIN mem_wdata[2]
    DIRECTION OUTPUT ;
    USE SIGNAL ;
    ANTENNADIFFAREA 2.673000 ;
    PORT
      LAYER met2 ;
        RECT 525.870 596.000 526.150 600.000 ;
    END
  END mem_wdata[2]
  PIN mem_wdata[30]
    DIRECTION OUTPUT ;
    USE SIGNAL ;
    ANTENNADIFFAREA 2.673000 ;
    PORT
      LAYER met2 ;
        RECT 172.590 596.000 172.870 600.000 ;
    END
  END mem_wdata[30]
  PIN mem_wdata[31]
    DIRECTION OUTPUT ;
    USE SIGNAL ;
    ANTENNADIFFAREA 2.673000 ;
    PORT
      LAYER met2 ;
        RECT 161.550 596.000 161.830 600.000 ;
    END
  END mem_wdata[31]
  PIN mem_wdata[3]
    DIRECTION OUTPUT ;
    USE SIGNAL ;
    ANTENNADIFFAREA 2.673000 ;
    PORT
      LAYER met2 ;
        RECT 503.790 596.000 504.070 600.000 ;
    END
  END mem_wdata[3]
  PIN mem_wdata[4]
    DIRECTION OUTPUT ;
    USE SIGNAL ;
    ANTENNADIFFAREA 2.673000 ;
    PORT
      LAYER met2 ;
        RECT 481.710 596.000 481.990 600.000 ;
    END
  END mem_wdata[4]
  PIN mem_wdata[5]
    DIRECTION OUTPUT ;
    USE SIGNAL ;
    ANTENNADIFFAREA 2.673000 ;
    PORT
      LAYER met2 ;
        RECT 465.150 596.000 465.430 600.000 ;
    END
  END mem_wdata[5]
  PIN mem_wdata[6]
    DIRECTION OUTPUT ;
    USE SIGNAL ;
    ANTENNADIFFAREA 2.673000 ;
    PORT
      LAYER met2 ;
        RECT 448.590 596.000 448.870 600.000 ;
    END
  END mem_wdata[6]
  PIN mem_wdata[7]
    DIRECTION OUTPUT ;
    USE SIGNAL ;
    ANTENNADIFFAREA 2.673000 ;
    PORT
      LAYER met2 ;
        RECT 432.030 596.000 432.310 600.000 ;
    END
  END mem_wdata[7]
  PIN mem_wdata[8]
    DIRECTION OUTPUT ;
    USE SIGNAL ;
    ANTENNADIFFAREA 2.673000 ;
    PORT
      LAYER met2 ;
        RECT 415.470 596.000 415.750 600.000 ;
    END
  END mem_wdata[8]
  PIN mem_wdata[9]
    DIRECTION OUTPUT ;
    USE SIGNAL ;
    ANTENNADIFFAREA 2.673000 ;
    PORT
      LAYER met2 ;
        RECT 404.430 596.000 404.710 600.000 ;
    END
  END mem_wdata[9]
  PIN mem_we[0]
    DIRECTION OUTPUT ;
    USE SIGNAL ;
    ANTENNADIFFAREA 2.673000 ;
    PORT
      LAYER met2 ;
        RECT 564.510 596.000 564.790 600.000 ;
    END
  END mem_we[0]
  PIN mem_we[1]
    DIRECTION OUTPUT ;
    USE SIGNAL ;
    ANTENNADIFFAREA 2.673000 ;
    PORT
      LAYER met2 ;
        RECT 542.430 596.000 542.710 600.000 ;
    END
  END mem_we[1]
  PIN mem_we[2]
    DIRECTION OUTPUT ;
    USE SIGNAL ;
    ANTENNADIFFAREA 2.673000 ;
    PORT
      LAYER met2 ;
        RECT 520.350 596.000 520.630 600.000 ;
    END
  END mem_we[2]
  PIN mem_we[3]
    DIRECTION OUTPUT ;
    USE SIGNAL ;
    ANTENNADIFFAREA 2.673000 ;
    PORT
      LAYER met2 ;
        RECT 498.270 596.000 498.550 600.000 ;
    END
  END mem_we[3]
  PIN rst_n
    DIRECTION INPUT ;
    USE SIGNAL ;
    ANTENNAGATEAREA 0.647700 ;
    ANTENNADIFFAREA 0.434700 ;
    PORT
      LAYER met2 ;
        RECT 538.750 0.000 539.030 4.000 ;
    END
  END rst_n
  PIN vccd1
    DIRECTION INOUT ;
    USE POWER ;
    PORT
      LAYER met4 ;
        RECT 21.040 10.640 22.640 587.760 ;
    END
    PORT
      LAYER met4 ;
        RECT 174.640 10.640 176.240 587.760 ;
    END
    PORT
      LAYER met4 ;
        RECT 328.240 10.640 329.840 587.760 ;
    END
    PORT
      LAYER met4 ;
        RECT 481.840 10.640 483.440 587.760 ;
    END
  END vccd1
  PIN vssd1
    DIRECTION INOUT ;
    USE GROUND ;
    PORT
      LAYER met4 ;
        RECT 24.340 10.640 25.940 587.760 ;
    END
    PORT
      LAYER met4 ;
        RECT 177.940 10.640 179.540 587.760 ;
    END
    PORT
      LAYER met4 ;
        RECT 331.540 10.640 333.140 587.760 ;
    END
    PORT
      LAYER met4 ;
        RECT 485.140 10.640 486.740 587.760 ;
    END
  END vssd1
  OBS
      LAYER nwell ;
        RECT 5.330 10.760 594.510 587.640 ;
      LAYER li1 ;
        RECT 5.520 10.795 594.320 587.605 ;
      LAYER met1 ;
        RECT 4.210 0.380 594.320 590.200 ;
      LAYER met2 ;
        RECT 4.230 595.720 12.230 596.770 ;
        RECT 13.070 595.720 17.750 596.770 ;
        RECT 18.590 595.720 23.270 596.770 ;
        RECT 24.110 595.720 28.790 596.770 ;
        RECT 29.630 595.720 34.310 596.770 ;
        RECT 35.150 595.720 39.830 596.770 ;
        RECT 40.670 595.720 45.350 596.770 ;
        RECT 46.190 595.720 50.870 596.770 ;
        RECT 51.710 595.720 56.390 596.770 ;
        RECT 57.230 595.720 61.910 596.770 ;
        RECT 62.750 595.720 67.430 596.770 ;
        RECT 68.270 595.720 72.950 596.770 ;
        RECT 73.790 595.720 78.470 596.770 ;
        RECT 79.310 595.720 83.990 596.770 ;
        RECT 84.830 595.720 89.510 596.770 ;
        RECT 90.350 595.720 95.030 596.770 ;
        RECT 95.870 595.720 100.550 596.770 ;
        RECT 101.390 595.720 106.070 596.770 ;
        RECT 106.910 595.720 111.590 596.770 ;
        RECT 112.430 595.720 117.110 596.770 ;
        RECT 117.950 595.720 122.630 596.770 ;
        RECT 123.470 595.720 128.150 596.770 ;
        RECT 128.990 595.720 133.670 596.770 ;
        RECT 134.510 595.720 139.190 596.770 ;
        RECT 140.030 595.720 144.710 596.770 ;
        RECT 145.550 595.720 150.230 596.770 ;
        RECT 151.070 595.720 155.750 596.770 ;
        RECT 156.590 595.720 161.270 596.770 ;
        RECT 162.110 595.720 166.790 596.770 ;
        RECT 167.630 595.720 172.310 596.770 ;
        RECT 173.150 595.720 177.830 596.770 ;
        RECT 178.670 595.720 183.350 596.770 ;
        RECT 184.190 595.720 188.870 596.770 ;
        RECT 189.710 595.720 194.390 596.770 ;
        RECT 195.230 595.720 199.910 596.770 ;
        RECT 200.750 595.720 205.430 596.770 ;
        RECT 206.270 595.720 210.950 596.770 ;
        RECT 211.790 595.720 216.470 596.770 ;
        RECT 217.310 595.720 221.990 596.770 ;
        RECT 222.830 595.720 227.510 596.770 ;
        RECT 228.350 595.720 233.030 596.770 ;
        RECT 233.870 595.720 238.550 596.770 ;
        RECT 239.390 595.720 244.070 596.770 ;
        RECT 244.910 595.720 249.590 596.770 ;
        RECT 250.430 595.720 255.110 596.770 ;
        RECT 255.950 595.720 260.630 596.770 ;
        RECT 261.470 595.720 266.150 596.770 ;
        RECT 266.990 595.720 271.670 596.770 ;
        RECT 272.510 595.720 277.190 596.770 ;
        RECT 278.030 595.720 282.710 596.770 ;
        RECT 283.550 595.720 288.230 596.770 ;
        RECT 289.070 595.720 293.750 596.770 ;
        RECT 294.590 595.720 299.270 596.770 ;
        RECT 300.110 595.720 304.790 596.770 ;
        RECT 305.630 595.720 310.310 596.770 ;
        RECT 311.150 595.720 315.830 596.770 ;
        RECT 316.670 595.720 321.350 596.770 ;
        RECT 322.190 595.720 326.870 596.770 ;
        RECT 327.710 595.720 332.390 596.770 ;
        RECT 333.230 595.720 337.910 596.770 ;
        RECT 338.750 595.720 343.430 596.770 ;
        RECT 344.270 595.720 348.950 596.770 ;
        RECT 349.790 595.720 354.470 596.770 ;
        RECT 355.310 595.720 359.990 596.770 ;
        RECT 360.830 595.720 365.510 596.770 ;
        RECT 366.350 595.720 371.030 596.770 ;
        RECT 371.870 595.720 376.550 596.770 ;
        RECT 377.390 595.720 382.070 596.770 ;
        RECT 382.910 595.720 387.590 596.770 ;
        RECT 388.430 595.720 393.110 596.770 ;
        RECT 393.950 595.720 398.630 596.770 ;
        RECT 399.470 595.720 404.150 596.770 ;
        RECT 404.990 595.720 409.670 596.770 ;
        RECT 410.510 595.720 415.190 596.770 ;
        RECT 416.030 595.720 420.710 596.770 ;
        RECT 421.550 595.720 426.230 596.770 ;
        RECT 427.070 595.720 431.750 596.770 ;
        RECT 432.590 595.720 437.270 596.770 ;
        RECT 438.110 595.720 442.790 596.770 ;
        RECT 443.630 595.720 448.310 596.770 ;
        RECT 449.150 595.720 453.830 596.770 ;
        RECT 454.670 595.720 459.350 596.770 ;
        RECT 460.190 595.720 464.870 596.770 ;
        RECT 465.710 595.720 470.390 596.770 ;
        RECT 471.230 595.720 475.910 596.770 ;
        RECT 476.750 595.720 481.430 596.770 ;
        RECT 482.270 595.720 486.950 596.770 ;
        RECT 487.790 595.720 492.470 596.770 ;
        RECT 493.310 595.720 497.990 596.770 ;
        RECT 498.830 595.720 503.510 596.770 ;
        RECT 504.350 595.720 509.030 596.770 ;
        RECT 509.870 595.720 514.550 596.770 ;
        RECT 515.390 595.720 520.070 596.770 ;
        RECT 520.910 595.720 525.590 596.770 ;
        RECT 526.430 595.720 531.110 596.770 ;
        RECT 531.950 595.720 536.630 596.770 ;
        RECT 537.470 595.720 542.150 596.770 ;
        RECT 542.990 595.720 547.670 596.770 ;
        RECT 548.510 595.720 553.190 596.770 ;
        RECT 554.030 595.720 558.710 596.770 ;
        RECT 559.550 595.720 564.230 596.770 ;
        RECT 565.070 595.720 569.750 596.770 ;
        RECT 570.590 595.720 575.270 596.770 ;
        RECT 576.110 595.720 580.790 596.770 ;
        RECT 581.630 595.720 586.310 596.770 ;
        RECT 587.150 595.720 592.390 596.770 ;
        RECT 4.230 4.280 592.390 595.720 ;
        RECT 4.230 0.350 60.070 4.280 ;
        RECT 60.910 0.350 179.670 4.280 ;
        RECT 180.510 0.350 299.270 4.280 ;
        RECT 300.110 0.350 418.870 4.280 ;
        RECT 419.710 0.350 538.470 4.280 ;
        RECT 539.310 0.350 592.390 4.280 ;
      LAYER met3 ;
        RECT 3.990 579.040 596.000 587.685 ;
        RECT 4.400 577.640 596.000 579.040 ;
        RECT 3.990 569.520 596.000 577.640 ;
        RECT 3.990 568.120 595.600 569.520 ;
        RECT 3.990 565.440 596.000 568.120 ;
        RECT 4.400 564.040 596.000 565.440 ;
        RECT 3.990 557.280 596.000 564.040 ;
        RECT 3.990 555.880 595.600 557.280 ;
        RECT 3.990 551.840 596.000 555.880 ;
        RECT 4.400 550.440 596.000 551.840 ;
        RECT 3.990 545.040 596.000 550.440 ;
        RECT 3.990 543.640 595.600 545.040 ;
        RECT 3.990 538.240 596.000 543.640 ;
        RECT 4.400 536.840 596.000 538.240 ;
        RECT 3.990 532.800 596.000 536.840 ;
        RECT 3.990 531.400 595.600 532.800 ;
        RECT 3.990 524.640 596.000 531.400 ;
        RECT 4.400 523.240 596.000 524.640 ;
        RECT 3.990 520.560 596.000 523.240 ;
        RECT 3.990 519.160 595.600 520.560 ;
        RECT 3.990 511.040 596.000 519.160 ;
        RECT 4.400 509.640 596.000 511.040 ;
        RECT 3.990 508.320 596.000 509.640 ;
        RECT 3.990 506.920 595.600 508.320 ;
        RECT 3.990 497.440 596.000 506.920 ;
        RECT 4.400 496.080 596.000 497.440 ;
        RECT 4.400 496.040 595.600 496.080 ;
        RECT 3.990 494.680 595.600 496.040 ;
        RECT 3.990 483.840 596.000 494.680 ;
        RECT 4.400 482.440 595.600 483.840 ;
        RECT 3.990 471.600 596.000 482.440 ;
        RECT 3.990 470.240 595.600 471.600 ;
        RECT 4.400 470.200 595.600 470.240 ;
        RECT 4.400 468.840 596.000 470.200 ;
        RECT 3.990 459.360 596.000 468.840 ;
        RECT 3.990 457.960 595.600 459.360 ;
        RECT 3.990 456.640 596.000 457.960 ;
        RECT 4.400 455.240 596.000 456.640 ;
        RECT 3.990 447.120 596.000 455.240 ;
        RECT 3.990 445.720 595.600 447.120 ;
        RECT 3.990 443.040 596.000 445.720 ;
        RECT 4.400 441.640 596.000 443.040 ;
        RECT 3.990 434.880 596.000 441.640 ;
        RECT 3.990 433.480 595.600 434.880 ;
        RECT 3.990 429.440 596.000 433.480 ;
        RECT 4.400 428.040 596.000 429.440 ;
        RECT 3.990 422.640 596.000 428.040 ;
        RECT 3.990 421.240 595.600 422.640 ;
        RECT 3.990 415.840 596.000 421.240 ;
        RECT 4.400 414.440 596.000 415.840 ;
        RECT 3.990 410.400 596.000 414.440 ;
        RECT 3.990 409.000 595.600 410.400 ;
        RECT 3.990 402.240 596.000 409.000 ;
        RECT 4.400 400.840 596.000 402.240 ;
        RECT 3.990 398.160 596.000 400.840 ;
        RECT 3.990 396.760 595.600 398.160 ;
        RECT 3.990 388.640 596.000 396.760 ;
        RECT 4.400 387.240 596.000 388.640 ;
        RECT 3.990 385.920 596.000 387.240 ;
        RECT 3.990 384.520 595.600 385.920 ;
        RECT 3.990 375.040 596.000 384.520 ;
        RECT 4.400 373.680 596.000 375.040 ;
        RECT 4.400 373.640 595.600 373.680 ;
        RECT 3.990 372.280 595.600 373.640 ;
        RECT 3.990 361.440 596.000 372.280 ;
        RECT 4.400 360.040 595.600 361.440 ;
        RECT 3.990 349.200 596.000 360.040 ;
        RECT 3.990 347.840 595.600 349.200 ;
        RECT 4.400 347.800 595.600 347.840 ;
        RECT 4.400 346.440 596.000 347.800 ;
        RECT 3.990 336.960 596.000 346.440 ;
        RECT 3.990 335.560 595.600 336.960 ;
        RECT 3.990 334.240 596.000 335.560 ;
        RECT 4.400 332.840 596.000 334.240 ;
        RECT 3.990 324.720 596.000 332.840 ;
        RECT 3.990 323.320 595.600 324.720 ;
        RECT 3.990 320.640 596.000 323.320 ;
        RECT 4.400 319.240 596.000 320.640 ;
        RECT 3.990 312.480 596.000 319.240 ;
        RECT 3.990 311.080 595.600 312.480 ;
        RECT 3.990 307.040 596.000 311.080 ;
        RECT 4.400 305.640 596.000 307.040 ;
        RECT 3.990 300.240 596.000 305.640 ;
        RECT 3.990 298.840 595.600 300.240 ;
        RECT 3.990 293.440 596.000 298.840 ;
        RECT 4.400 292.040 596.000 293.440 ;
        RECT 3.990 288.000 596.000 292.040 ;
        RECT 3.990 286.600 595.600 288.000 ;
        RECT 3.990 279.840 596.000 286.600 ;
        RECT 4.400 278.440 596.000 279.840 ;
        RECT 3.990 275.760 596.000 278.440 ;
        RECT 3.990 274.360 595.600 275.760 ;
        RECT 3.990 266.240 596.000 274.360 ;
        RECT 4.400 264.840 596.000 266.240 ;
        RECT 3.990 263.520 596.000 264.840 ;
        RECT 3.990 262.120 595.600 263.520 ;
        RECT 3.990 252.640 596.000 262.120 ;
        RECT 4.400 251.280 596.000 252.640 ;
        RECT 4.400 251.240 595.600 251.280 ;
        RECT 3.990 249.880 595.600 251.240 ;
        RECT 3.990 239.040 596.000 249.880 ;
        RECT 4.400 237.640 595.600 239.040 ;
        RECT 3.990 226.800 596.000 237.640 ;
        RECT 3.990 225.440 595.600 226.800 ;
        RECT 4.400 225.400 595.600 225.440 ;
        RECT 4.400 224.040 596.000 225.400 ;
        RECT 3.990 214.560 596.000 224.040 ;
        RECT 3.990 213.160 595.600 214.560 ;
        RECT 3.990 211.840 596.000 213.160 ;
        RECT 4.400 210.440 596.000 211.840 ;
        RECT 3.990 202.320 596.000 210.440 ;
        RECT 3.990 200.920 595.600 202.320 ;
        RECT 3.990 198.240 596.000 200.920 ;
        RECT 4.400 196.840 596.000 198.240 ;
        RECT 3.990 190.080 596.000 196.840 ;
        RECT 3.990 188.680 595.600 190.080 ;
        RECT 3.990 184.640 596.000 188.680 ;
        RECT 4.400 183.240 596.000 184.640 ;
        RECT 3.990 177.840 596.000 183.240 ;
        RECT 3.990 176.440 595.600 177.840 ;
        RECT 3.990 171.040 596.000 176.440 ;
        RECT 4.400 169.640 596.000 171.040 ;
        RECT 3.990 165.600 596.000 169.640 ;
        RECT 3.990 164.200 595.600 165.600 ;
        RECT 3.990 157.440 596.000 164.200 ;
        RECT 4.400 156.040 596.000 157.440 ;
        RECT 3.990 153.360 596.000 156.040 ;
        RECT 3.990 151.960 595.600 153.360 ;
        RECT 3.990 143.840 596.000 151.960 ;
        RECT 4.400 142.440 596.000 143.840 ;
        RECT 3.990 141.120 596.000 142.440 ;
        RECT 3.990 139.720 595.600 141.120 ;
        RECT 3.990 130.240 596.000 139.720 ;
        RECT 4.400 128.880 596.000 130.240 ;
        RECT 4.400 128.840 595.600 128.880 ;
        RECT 3.990 127.480 595.600 128.840 ;
        RECT 3.990 116.640 596.000 127.480 ;
        RECT 4.400 115.240 595.600 116.640 ;
        RECT 3.990 104.400 596.000 115.240 ;
        RECT 3.990 103.040 595.600 104.400 ;
        RECT 4.400 103.000 595.600 103.040 ;
        RECT 4.400 101.640 596.000 103.000 ;
        RECT 3.990 92.160 596.000 101.640 ;
        RECT 3.990 90.760 595.600 92.160 ;
        RECT 3.990 89.440 596.000 90.760 ;
        RECT 4.400 88.040 596.000 89.440 ;
        RECT 3.990 79.920 596.000 88.040 ;
        RECT 3.990 78.520 595.600 79.920 ;
        RECT 3.990 75.840 596.000 78.520 ;
        RECT 4.400 74.440 596.000 75.840 ;
        RECT 3.990 67.680 596.000 74.440 ;
        RECT 3.990 66.280 595.600 67.680 ;
        RECT 3.990 62.240 596.000 66.280 ;
        RECT 4.400 60.840 596.000 62.240 ;
        RECT 3.990 55.440 596.000 60.840 ;
        RECT 3.990 54.040 595.600 55.440 ;
        RECT 3.990 48.640 596.000 54.040 ;
        RECT 4.400 47.240 596.000 48.640 ;
        RECT 3.990 43.200 596.000 47.240 ;
        RECT 3.990 41.800 595.600 43.200 ;
        RECT 3.990 35.040 596.000 41.800 ;
        RECT 4.400 33.640 596.000 35.040 ;
        RECT 3.990 30.960 596.000 33.640 ;
        RECT 3.990 29.560 595.600 30.960 ;
        RECT 3.990 21.440 596.000 29.560 ;
        RECT 4.400 20.040 596.000 21.440 ;
        RECT 3.990 10.715 596.000 20.040 ;
      LAYER met4 ;
        RECT 43.535 13.095 174.240 579.865 ;
        RECT 176.640 13.095 177.540 579.865 ;
        RECT 179.940 13.095 327.840 579.865 ;
        RECT 330.240 13.095 331.140 579.865 ;
        RECT 333.540 13.095 481.440 579.865 ;
        RECT 483.840 13.095 484.740 579.865 ;
        RECT 487.140 13.095 571.025 579.865 ;
  END
END picorv32_soc
END LIBRARY

